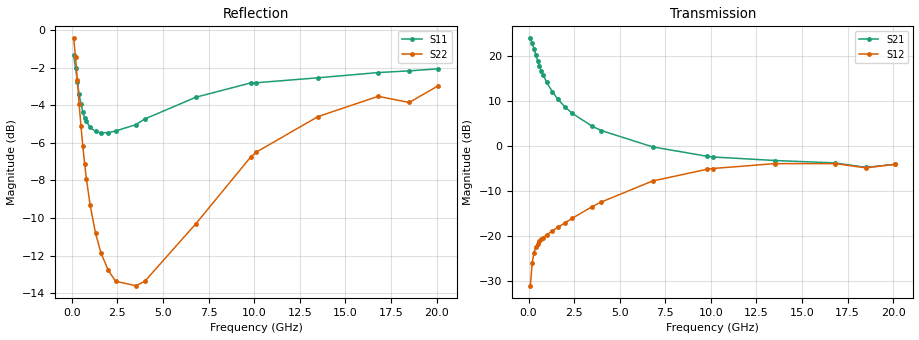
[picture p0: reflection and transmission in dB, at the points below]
!  Infineon Technologies AG
! BFR380L3 , PF131585-7, No.6, Th 09.10.01, soldered on pcb-board, measured with PP GSG850
!  Vce=3.0 V,  Ic=5.0 mA
! Common Emitter S-Parameters:  15. November 2001
#  GHz  S  MA  R  50
! f  S11  S21  S12  S22
! GHz  Mag  Ang  Mag  Ang  Mag  Ang  Mag  Ang
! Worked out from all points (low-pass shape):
!   201 points, 100 MHz to 20.1 GHz, reference 50 ohm
!   highest |S21| = 23.99 dB at 100 MHz (marker M1); lowest = -4.7 dB at 18.5 GHz (marker M2)
!   |S21| within 3 dB of the highest: start of sweep to 347.9 MHz
!   lowest |S11| = -5.5 dB at 1.6 GHz (marker M3), VSWR 3.28, Z = 15.3 - j3.5 ohm
!   |S11| at or under -10 dB: nowhere
!   |S22| runs from -13.7 to -0.4 dB; largest |S21 - S12| = 16
!   S11 on the Smith chart (normalised r, x): 100 MHz: 1.21, -3.63; 400 MHz: 0.37, -0.91; 1 GHz: 0.31, -0.28; 4 GHz: 0.30, +0.34; 9.8 GHz: 0.38, +1.13; 20.1 GHz: 0.99, +2.55
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0.1  0.8556 -28.0  15.83 161.0  0.02803 74.1  0.9496 -17.0
0.2  0.7935 -53.4  13.97 145.0  0.05001 63.0  0.8474 -31.2
0.3  0.7286 -74.6  12.05 132.5  0.06544 54.9  0.7343 -41.9
0.4  0.6747 -91.3  10.36 122.8  0.07527 49.3  0.6347 -49.7
0.5  0.6359 -104.8  8.953 115.3  0.08232 46.1  0.5548 -55.5
0.6  0.6059 -116.1  7.831 109.2  0.08797 43.8  0.4915 -59.9
0.7  0.5842 -125.3  6.941 104.2  0.09241 42.5  0.4411 -63.3
0.8  0.5713 -133.4  6.212 99.9  0.09629 41.9  0.4016 -66.1
1  0.5507 -146.0  5.12 92.8  0.1033 41.8  0.3427 -70.5
1.3  0.5374 -160.2  4.047 84.4  0.1137 43.0  0.2883 -75.6
1.6  0.5325 -171.2  3.35 77.4  0.1246 44.8  0.2552 -80.1
2  0.5336 177.5  2.731 69.5  0.1402 46.9  0.2296 -86.2
2.4  0.5389 168.1  2.316 62.4  0.1578 48.6  0.2149 -92.5
3.5  0.5599 147.3  1.662 45.6  0.2129 50.2  0.2092 -111.8
4  0.58 139.7  1.491 39.2  0.2396 49.8  0.2149 -122.6
6.8  0.6625 105.1  0.9823 10.7  0.4098 37.0  0.3056 -175.8
9.799999  0.7229 79.6  0.7714 -6.9  0.554 16.4  0.4592 141.8
10.1  0.7237 77.4  0.7584 -8.0  0.5642 14.4  0.4731 138.1
13.5  0.7462 59.5  0.6927 -21.8  0.6392 -8.4  0.5887 103.7
16.8  0.7704 47.2  0.6515 -33.0  0.6396 -25.3  0.6662 79.6
18.5  0.7784 45.1  0.581 -40.5  0.5739 -34.0  0.6416 73.4
20.1  0.7884 38.2  0.6276 -43.7  0.628 -39.1  0.7114 62.2
